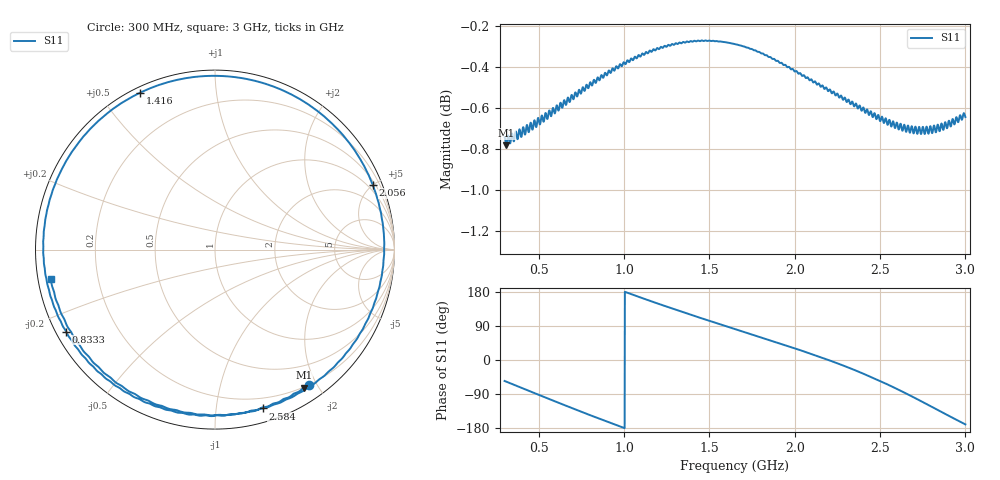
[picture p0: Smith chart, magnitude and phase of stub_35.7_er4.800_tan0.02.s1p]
! Chirptenna · simulación 3D de un stub abierto
# HZ S RI R 50
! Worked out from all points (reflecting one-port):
!   2001 points, 300 MHz to 3 GHz, reference 50 ohm
!   lowest |S11| = -0.8 dB at 310.8 MHz (marker M1), VSWR 22.24, Z = 9.72 - j90.8 ohm
!   phase of S11 starts at -55 deg and turns -475 deg over the sweep
!   S11 on the Smith chart (normalised r, x): 300 MHz: 0.20, -1.89; 833.2 MHz: 0.03, -0.26; 1.416 GHz: 0.02, +0.63; 2.056 GHz: 0.67, +4.99; 2.584 GHz: 0.11, -1.34; 3 GHz: 0.04, -0.09
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3e8  0.5225 -0.7549
3.108e8  0.4941 -0.7689
3.9855e8  0.263 -0.8797
4.836e8  0.0168 -0.9232
5.5245e8  -0.1823 -0.9097
6.375e8  -0.4192 -0.8338
7.239e8  -0.6291 -0.6974
8.3325e8  -0.8286 -0.4572
9.75e8  -0.9528 -0.0816
1.0533e9  -0.9492 0.1335
1.137e9  -0.8951 0.353
1.2234e9  -0.7895 0.5552
1.3125e9  -0.6372 0.7276
1.41645e9  -0.4188 0.8736
1.53255e9  -0.1447 0.9578
1.65e9  0.1408 0.9568
1.81335e9  0.5075 0.8173
1.9875e9  0.8025 0.5154
2.05635e9  0.8792 0.3605
2.1954e9  0.942 0.00522
2.325e9  0.8676 -0.3493
2.45325e9  0.644 -0.6698
2.5842e9  0.265 -0.8847
2.6625e9  -0.0102 -0.9239
2.73675e9  -0.2835 -0.8757
2.8056e9  -0.5163 -0.7617
2.9136e9  -0.7985 -0.4641
3e9  -0.9142 -0.1624
